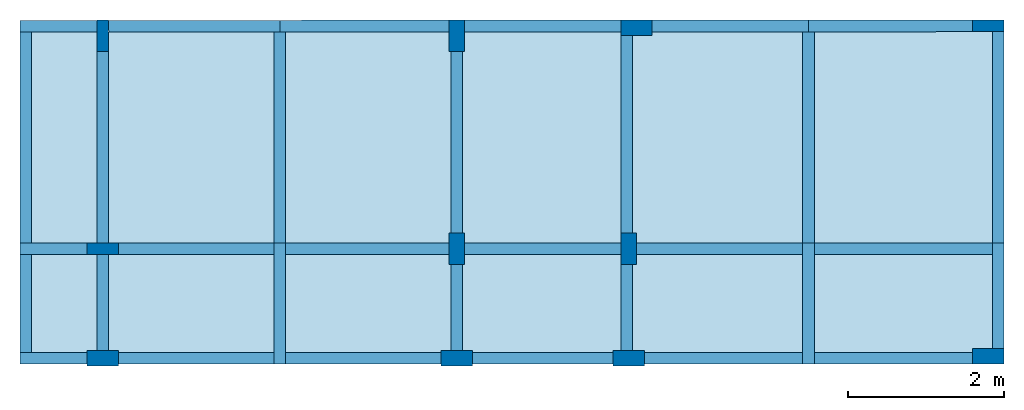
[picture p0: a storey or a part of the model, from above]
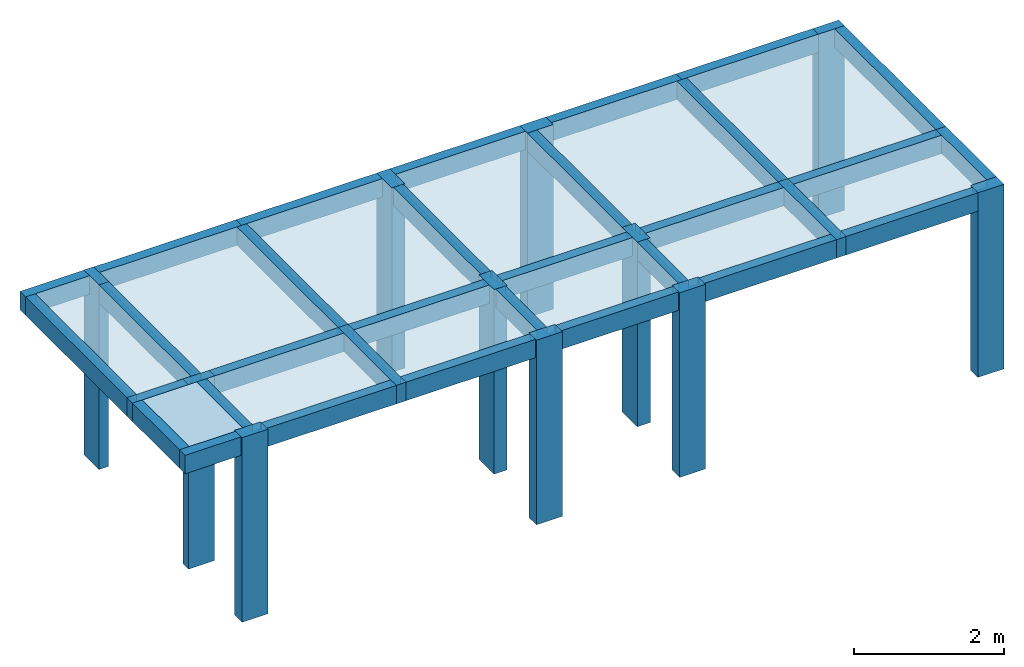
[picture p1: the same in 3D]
Properties of the parts of a building model (IFC2X3)

# File
Description: IFC2X3
Time: 2025-07-01T16:00:53
Made in: IfcPlusPlus

# IfcBuildingStorey (6)
Name | LongName | Elevation (cm)
01. Estacionamento | 01. Estacionamento | 0
02. Térreo | 02. Térreo | 80
03. Pavimento Superior | 03. Pavimento Superior | 400
04. Cobertura | 04. Cobertura | 720
05. Pavimento Técnico | 05. Pavimento Técnico | 1020
06. Laje do Pavimento Técnico | 06. Laje do Pavimento Técnico | 1320

# IfcBeam (464)
Material: Concreto
Pset_ConcreteElementGeneral - EnvironmentalClass: 2; ConstructionType: InSitu
AltoQi_Eberick_Elemento - Elemento: Viga; Tipo: retangular; Elevação: 0 cm
AltoQi_Eberick_Padrão - Ambiente: Externo; Cobrimento: 3 cm; Classe de concreto: C-25
AltoQi_Eberick_Cargas - Cargas de parede (G2): 0; Adicional (G2): 0; Solo (S): 0; Acidental (Q): 0; Água (A): 0; Subpressão (AS): 0
Pset_BeamCommon - IsExternal: yes; LoadBearing: yes
Name | In | Seção_bw (cm) | Seção_h (cm) | Taxa de armadura | Reference
6 x V1 | 02. Térreo | 15 | 40 | 0.17 % | Viga C-25 - Seção Retangular 15 X 40
V1 | 02. Térreo | 15 | 40 | 1.34 % | Viga C-25 - Seção Retangular 15 X 40
V10 | 02. Térreo | 15 | 40 | 0.17 % | Viga C-25 - Seção Retangular 15 X 40
V10 | 02. Térreo | 15 | 40 | 0.26 % | Viga C-25 - Seção Retangular 15 X 40
2 x V11 | 02. Térreo | 15 | 40 | 0.26 % | Viga C-25 - Seção Retangular 15 X 40
V11 | 02. Térreo | 15 | 40 | 0.17 % | Viga C-25 - Seção Retangular 15 X 40
5 x V12 | 02. Térreo | 15 | 40 | 0.17 % | Viga C-25 - Seção Retangular 15 X 40
V13 | 02. Térreo | 15 | 40 | 0.34 % | Viga C-25 - Seção Retangular 15 X 40
V13 | 02. Térreo | 15 | 40 | 0.52 % | Viga C-25 - Seção Retangular 15 X 40
2 x V14 | 02. Térreo | 15 | 40 | 0.34 % | Viga C-25 - Seção Retangular 15 X 40
V14 | 02. Térreo | 15 | 40 | 0.50 % | Viga C-25 - Seção Retangular 15 X 40
V15 | 02. Térreo | 15 | 40 | 0.52 % | Viga C-25 - Seção Retangular 15 X 40
2 x V15 | 02. Térreo | 15 | 40 | 0.26 % | Viga C-25 - Seção Retangular 15 X 40
V16 | 02. Térreo | 15 | 40 | 0.65 % | Viga C-25 - Seção Retangular 15 X 40
V16 | 02. Térreo | 15 | 40 | 0.25 % | Viga C-25 - Seção Retangular 15 X 40
V16 | 02. Térreo | 15 | 40 | 0.41 % | Viga C-25 - Seção Retangular 15 X 40
V17 | 02. Térreo | 15 | 40 | 0.17 % | Viga C-25 - Seção Retangular 15 X 40
V17 | 02. Térreo | 15 | 40 | 0.25 % | Viga C-25 - Seção Retangular 15 X 40
2 x V18 | 02. Térreo | 20 | 40 | 0.59 % | Viga C-25 - Seção Retangular 20 X 40
V18 | 02. Térreo | 20 | 40 | 0.69 % | Viga C-25 - Seção Retangular 20 X 40
4 x V19 | 02. Térreo | 20 | 40 | 0.88 % | Viga C-25 - Seção Retangular 20 X 40
V2 | 02. Térreo | 15 | 40 | 0.34 % | Viga C-25 - Seção Retangular 15 X 40
V2 | 02. Térreo | 15 | 40 | 1.34 % | Viga C-25 - Seção Retangular 15 X 40
2 x V2 | 02. Térreo | 15 | 40 | 0.17 % | Viga C-25 - Seção Retangular 15 X 40
V2 | 02. Térreo | 15 | 40 | 1.02 % | Viga C-25 - Seção Retangular 15 X 40
V20 | 02. Térreo | 20 | 40 | 0.44 % | Viga C-25 - Seção Retangular 20 X 40
2 x V21 | 02. Térreo | 30 | 60 | Não calculado | Viga C-25 - Seção Retangular 30 X 60
V22 | 02. Térreo | 30 | 60 | 0.17 % | Viga C-25 - Seção Retangular 30 X 60
V22 | 02. Térreo | 30 | 60 | 0.26 % | Viga C-25 - Seção Retangular 30 X 60
2 x V23 | 02. Térreo | 30 | 60 | 0.17 % | Viga C-25 - Seção Retangular 30 X 60
2 x V24 | 02. Térreo | 30 | 60 | 0.17 % | Viga C-25 - Seção Retangular 30 X 60
3 x V25 | 02. Térreo | 30 | 60 | Não calculado | Viga C-25 - Seção Retangular 30 X 60
3 x V26 | 02. Térreo | 15 | 40 | 0.59 % | Viga C-25 - Seção Retangular 15 X 40
V27 | 02. Térreo | 15 | 40 | 1.01 % | Viga C-25 - Seção Retangular 15 X 40
V28 | 02. Térreo | 15 | 40 | 0.17 % | Viga C-25 - Seção Retangular 15 X 40
V29 | 02. Térreo | 20 | 40 | Não calculado | Viga C-25 - Seção Retangular 20 X 40
4 x V3 | 02. Térreo | 15 | 40 | 0.17 % | Viga C-25 - Seção Retangular 15 X 40
V33 | 02. Térreo | 25 | 60 | 0.16 % | Viga C-25 - Seção Retangular 25 X 60
2 x V4 | 02. Térreo | 15 | 40 | 0.34 % | Viga C-25 - Seção Retangular 15 X 40
3 x V4 | 02. Térreo | 15 | 40 | 0.17 % | Viga C-25 - Seção Retangular 15 X 40
V4 | 02. Térreo | 15 | 40 | 0.25 % | Viga C-25 - Seção Retangular 15 X 40
2 x V5 | 02. Térreo | 15 | 40 | 0.17 % | Viga C-25 - Seção Retangular 15 X 40
2 x V6 | 02. Térreo | 15 | 40 | 0.17 % | Viga C-25 - Seção Retangular 15 X 40
V8 | 02. Térreo | 15 | 40 | 3.02 % | Viga C-25 - Seção Retangular 15 X 40
2 x V8 | 02. Térreo | 15 | 40 | 1.34 % | Viga C-25 - Seção Retangular 15 X 40
V8 | 02. Térreo | 15 | 40 | 0.79 % | Viga C-25 - Seção Retangular 15 X 40
V8 | 02. Térreo | 15 | 40 | 1.68 % | Viga C-25 - Seção Retangular 15 X 40
V8 | 02. Térreo | 15 | 40 | 0.17 % | Viga C-25 - Seção Retangular 15 X 40
6 x V1 | 03. Pavimento Superior | 15 | 40 | 0.17 % | Viga C-25 - Seção Retangular 15 X 40
5 x V1 | 03. Pavimento Superior | 15 | 40 | 0.92 % | Viga C-25 - Seção Retangular 15 X 40
V10 | 03. Pavimento Superior | 20 | 40 | 0.38 % | Viga C-25 - Seção Retangular 20 X 40
V10 | 03. Pavimento Superior | 20 | 40 | 0.19 % | Viga C-25 - Seção Retangular 20 X 40
V10 | 03. Pavimento Superior | 20 | 40 | 0.88 % | Viga C-25 - Seção Retangular 20 X 40
V10 | 03. Pavimento Superior | 20 | 40 | 0.20 % | Viga C-25 - Seção Retangular 20 X 40
V10 | 03. Pavimento Superior | 20 | 40 | 0.29 % | Viga C-25 - Seção Retangular 20 X 40
V11 | 03. Pavimento Superior | 20 | 40 | 0.19 % | Viga C-25 - Seção Retangular 20 X 40
V12 | 03. Pavimento Superior | 20 | 40 | 0.69 % | Viga C-25 - Seção Retangular 20 X 40
V13 | 03. Pavimento Superior | 20 | 40 | 0.75 % | Viga C-25 - Seção Retangular 20 X 40
V14 | 03. Pavimento Superior | 20 | 40 | 1.23 % | Viga C-25 - Seção Retangular 20 X 40
V15 | 03. Pavimento Superior | 20 | 40 | 0.19 % | Viga C-25 - Seção Retangular 20 X 40
V16 | 03. Pavimento Superior | 15 | 40 | 0.17 % | Viga C-25 - Seção Retangular 15 X 40
V16 | 03. Pavimento Superior | 15 | 40 | 0.26 % | Viga C-25 - Seção Retangular 15 X 40
2 x V17 | 03. Pavimento Superior | 15 | 40 | 0.26 % | Viga C-25 - Seção Retangular 15 X 40
V17 | 03. Pavimento Superior | 15 | 40 | 0.17 % | Viga C-25 - Seção Retangular 15 X 40
6 x V18 | 03. Pavimento Superior | 15 | 40 | 0.17 % | Viga C-25 - Seção Retangular 15 X 40
V19 | 03. Pavimento Superior | 15 | 40 | 0.34 % | Viga C-25 - Seção Retangular 15 X 40
V19 | 03. Pavimento Superior | 15 | 40 | 0.52 % | Viga C-25 - Seção Retangular 15 X 40
V2 | 03. Pavimento Superior | 15 | 40 | 1.23 % | Viga C-25 - Seção Retangular 15 X 40
2 x V2 | 03. Pavimento Superior | 15 | 40 | 0.17 % | Viga C-25 - Seção Retangular 15 X 40
V2 | 03. Pavimento Superior | 15 | 40 | 0.92 % | Viga C-25 - Seção Retangular 15 X 40
V2 | 03. Pavimento Superior | 15 | 40 | 0.26 % | Viga C-25 - Seção Retangular 15 X 40
V20 | 03. Pavimento Superior | 15 | 40 | 0.61 % | Viga C-25 - Seção Retangular 15 X 40
2 x V20 | 03. Pavimento Superior | 15 | 40 | 0.39 % | Viga C-25 - Seção Retangular 15 X 40
V21 | 03. Pavimento Superior | 15 | 40 | 0.50 % | Viga C-25 - Seção Retangular 15 X 40
V21 | 03. Pavimento Superior | 15 | 40 | 0.39 % | Viga C-25 - Seção Retangular 15 X 40
V21 | 03. Pavimento Superior | 15 | 40 | 0.79 % | Viga C-25 - Seção Retangular 15 X 40
V22 | 03. Pavimento Superior | 15 | 40 | 0.79 % | Viga C-25 - Seção Retangular 15 X 40
V22 | 03. Pavimento Superior | 15 | 40 | 0.25 % | Viga C-25 - Seção Retangular 15 X 40
V22 | 03. Pavimento Superior | 15 | 40 | 0.59 % | Viga C-25 - Seção Retangular 15 X 40
V23 | 03. Pavimento Superior | 15 | 40 | 0.17 % | Viga C-25 - Seção Retangular 15 X 40
V23 | 03. Pavimento Superior | 15 | 40 | 0.25 % | Viga C-25 - Seção Retangular 15 X 40
2 x V24 | 03. Pavimento Superior | 20 | 40 | 0.59 % | Viga C-25 - Seção Retangular 20 X 40
V24 | 03. Pavimento Superior | 20 | 40 | 0.92 % | Viga C-25 - Seção Retangular 20 X 40
3 x V25 | 03. Pavimento Superior | 20 | 40 | 0.59 % | Viga C-25 - Seção Retangular 20 X 40
2 x V26 | 03. Pavimento Superior | 20 | 40 | 0.61 % | Viga C-25 - Seção Retangular 20 X 40
2 x V27 | 03. Pavimento Superior | 15 | 40 | 0.34 % | Viga C-25 - Seção Retangular 15 X 40
V28 | 03. Pavimento Superior | 15 | 40 | 0.17 % | Viga C-25 - Seção Retangular 15 X 40
V29 | 03. Pavimento Superior | 15 | 40 | 0.17 % | Viga C-25 - Seção Retangular 15 X 40
3 x V3 | 03. Pavimento Superior | 15 | 40 | 0.17 % | Viga C-25 - Seção Retangular 15 X 40
2 x V30 | 03. Pavimento Superior | 15 | 40 | 0.50 % | Viga C-25 - Seção Retangular 15 X 40
V31 | 03. Pavimento Superior | 15 | 40 | 0.17 % | Viga C-25 - Seção Retangular 15 X 40
3 x V32 | 03. Pavimento Superior | 20 | 45 | 0.61 % | Viga C-25 - Seção Retangular 20 X 45
2 x V32 | 03. Pavimento Superior | 20 | 45 | 0.17 % | Viga C-25 - Seção Retangular 20 X 45
2 x V33 | 03. Pavimento Superior | 20 | 40 | 0.19 % | Viga C-25 - Seção Retangular 20 X 40
V33 | 03. Pavimento Superior | 20 | 40 | 0.44 % | Viga C-25 - Seção Retangular 20 X 40
V34 | 03. Pavimento Superior | 20 | 40 | 0.75 % | Viga C-25 - Seção Retangular 20 X 40
2 x V34 | 03. Pavimento Superior | 20 | 40 | 0.19 % | Viga C-25 - Seção Retangular 20 X 40
V35 | 03. Pavimento Superior | 20 | 40 | 1.01 % | Viga C-25 - Seção Retangular 20 X 40
2 x V35 | 03. Pavimento Superior | 20 | 40 | 0.19 % | Viga C-25 - Seção Retangular 20 X 40
2 x V36 | 03. Pavimento Superior | 20 | 40 | 0.88 % | Viga C-25 - Seção Retangular 20 X 40
V36 | 03. Pavimento Superior | 20 | 40 | 0.19 % | Viga C-25 - Seção Retangular 20 X 40
2 x V37 | 03. Pavimento Superior | 15 | 30 | 0.22 % | Viga C-25 - Seção Retangular 15 X 30
V38 | 03. Pavimento Superior | 20 | 40 | 1.01 % | Viga C-25 - Seção Retangular 20 X 40
V39 | 03. Pavimento Superior | 15 | 40 | 0.17 % | Viga C-25 - Seção Retangular 15 X 40
5 x V4 | 03. Pavimento Superior | 15 | 40 | 0.79 % | Viga C-25 - Seção Retangular 15 X 40
V40 | 03. Pavimento Superior | 20 | 40 | Não calculado | Viga C-25 - Seção Retangular 20 X 40
3 x V5 | 03. Pavimento Superior | 15 | 40 | 0.39 % | Viga C-25 - Seção Retangular 15 X 40
2 x V5 | 03. Pavimento Superior | 15 | 40 | 0.17 % | Viga C-25 - Seção Retangular 15 X 40
V5 | 03. Pavimento Superior | 15 | 40 | 0.25 % | Viga C-25 - Seção Retangular 15 X 40
2 x V6 | 03. Pavimento Superior | 15 | 40 | 1.34 % | Viga C-25 - Seção Retangular 15 X 40
2 x V7 | 03. Pavimento Superior | 15 | 40 | 0.25 % | Viga C-25 - Seção Retangular 15 X 40
2 x V8 | 03. Pavimento Superior | 15 | 40 | 0.17 % | Viga C-25 - Seção Retangular 15 X 40
2 x V9 | 03. Pavimento Superior | 20 | 40 | 0.61 % | Viga C-25 - Seção Retangular 20 X 40
5 x V1 | 04. Cobertura | 15 | 40 | 0.17 % | Viga C-25 - Seção Retangular 15 X 40
3 x V1 | 04. Cobertura | 15 | 40 | 0.82 % | Viga C-25 - Seção Retangular 15 X 40
3 x V10 | 04. Cobertura | 20 | 40 | 0.75 % | Viga C-25 - Seção Retangular 20 X 40
V11 | 04. Cobertura | 20 | 40 | 0.92 % | Viga C-25 - Seção Retangular 20 X 40
V11 | 04. Cobertura | 20 | 40 | 0.20 % | Viga C-25 - Seção Retangular 20 X 40
V11 | 04. Cobertura | 20 | 40 | 0.29 % | Viga C-25 - Seção Retangular 20 X 40
V11 | 04. Cobertura | 20 | 40 | 0.19 % | Viga C-25 - Seção Retangular 20 X 40
V11 | 04. Cobertura | 20 | 40 | 0.39 % | Viga C-25 - Seção Retangular 20 X 40
V12 | 04. Cobertura | 20 | 40 | 0.19 % | Viga C-25 - Seção Retangular 20 X 40
V13 | 04. Cobertura | 20 | 40 | 0.69 % | Viga C-25 - Seção Retangular 20 X 40
V14 | 04. Cobertura | 20 | 40 | 0.69 % | Viga C-25 - Seção Retangular 20 X 40
V15 | 04. Cobertura | 20 | 40 | 1.26 % | Viga C-25 - Seção Retangular 20 X 40
V16 | 04. Cobertura | 20 | 40 | 0.19 % | Viga C-25 - Seção Retangular 20 X 40
V17 | 04. Cobertura | 15 | 40 | 0.17 % | Viga C-25 - Seção Retangular 15 X 40
V17 | 04. Cobertura | 15 | 40 | 0.26 % | Viga C-25 - Seção Retangular 15 X 40
2 x V18 | 04. Cobertura | 15 | 40 | 0.26 % | Viga C-25 - Seção Retangular 15 X 40
V18 | 04. Cobertura | 15 | 40 | 0.17 % | Viga C-25 - Seção Retangular 15 X 40
5 x V19 | 04. Cobertura | 15 | 40 | 0.17 % | Viga C-25 - Seção Retangular 15 X 40
2 x V2 | 04. Cobertura | 15 | 40 | 0.25 % | Viga C-25 - Seção Retangular 15 X 40
V2 | 04. Cobertura | 15 | 40 | 0.17 % | Viga C-25 - Seção Retangular 15 X 40
V2 | 04. Cobertura | 15 | 40 | 1.31 % | Viga C-25 - Seção Retangular 15 X 40
V2 | 04. Cobertura | 15 | 40 | 0.92 % | Viga C-25 - Seção Retangular 15 X 40
V2 | 04. Cobertura | 15 | 40 | 0.26 % | Viga C-25 - Seção Retangular 15 X 40
2 x V20 | 04. Cobertura | 15 | 40 | 0.34 % | Viga C-25 - Seção Retangular 15 X 40
V20 | 04. Cobertura | 15 | 40 | 0.41 % | Viga C-25 - Seção Retangular 15 X 40
V21 | 04. Cobertura | 15 | 40 | 0.34 % | Viga C-25 - Seção Retangular 15 X 40
V21 | 04. Cobertura | 15 | 40 | 0.26 % | Viga C-25 - Seção Retangular 15 X 40
V21 | 04. Cobertura | 15 | 40 | 0.52 % | Viga C-25 - Seção Retangular 15 X 40
V22 | 04. Cobertura | 15 | 40 | 0.39 % | Viga C-25 - Seção Retangular 15 X 40
V22 | 04. Cobertura | 15 | 40 | 0.61 % | Viga C-25 - Seção Retangular 15 X 40
V22 | 04. Cobertura | 15 | 40 | 0.25 % | Viga C-25 - Seção Retangular 15 X 40
V23 | 04. Cobertura | 15 | 40 | 0.17 % | Viga C-25 - Seção Retangular 15 X 40
V23 | 04. Cobertura | 15 | 40 | 0.25 % | Viga C-25 - Seção Retangular 15 X 40
3 x V24 | 04. Cobertura | 20 | 40 | 0.59 % | Viga C-25 - Seção Retangular 20 X 40
3 x V25 | 04. Cobertura | 20 | 40 | 0.59 % | Viga C-25 - Seção Retangular 20 X 40
2 x V26 | 04. Cobertura | 20 | 40 | 0.38 % | Viga C-25 - Seção Retangular 20 X 40
2 x V27 | 04. Cobertura | 15 | 40 | 0.17 % | Viga C-25 - Seção Retangular 15 X 40
3 x V28 | 04. Cobertura | 15 | 30 | 1.57 % | Viga C-25 - Seção Retangular 15 X 30
V29 | 04. Cobertura | 15 | 30 | 0.22 % | Viga C-25 - Seção Retangular 15 X 30
3 x V3 | 04. Cobertura | 15 | 40 | 0.17 % | Viga C-25 - Seção Retangular 15 X 40
2 x V30 | 04. Cobertura | 20 | 40 | 0.19 % | Viga C-25 - Seção Retangular 20 X 40
3 x V30 | 04. Cobertura | 20 | 40 | 0.69 % | Viga C-25 - Seção Retangular 20 X 40
V31 | 04. Cobertura | 15 | 30 | 0.34 % | Viga C-25 - Seção Retangular 15 X 30
2 x V32 | 04. Cobertura | 20 | 40 | 0.19 % | Viga C-25 - Seção Retangular 20 X 40
2 x V32 | 04. Cobertura | 20 | 40 | 0.29 % | Viga C-25 - Seção Retangular 20 X 40
V33 | 04. Cobertura | 20 | 40 | 0.49 % | Viga C-25 - Seção Retangular 20 X 40
2 x V33 | 04. Cobertura | 20 | 40 | 0.19 % | Viga C-25 - Seção Retangular 20 X 40
2 x V34 | 04. Cobertura | 20 | 40 | 0.19 % | Viga C-25 - Seção Retangular 20 X 40
V34 | 04. Cobertura | 20 | 40 | 0.61 % | Viga C-25 - Seção Retangular 20 X 40
2 x V35 | 04. Cobertura | 20 | 40 | 0.49 % | Viga C-25 - Seção Retangular 20 X 40
V35 | 04. Cobertura | 20 | 40 | 0.19 % | Viga C-25 - Seção Retangular 20 X 40
2 x V36 | 04. Cobertura | 15 | 30 | 0.22 % | Viga C-25 - Seção Retangular 15 X 30
V37 | 04. Cobertura | 15 | 40 | 0.79 % | Viga C-25 - Seção Retangular 15 X 40
V38 | 04. Cobertura | 15 | 40 | 0.17 % | Viga C-25 - Seção Retangular 15 X 40
V39 | 04. Cobertura | 15 | 40 | Não calculado | Viga C-25 - Seção Retangular 15 X 40
3 x V4 | 04. Cobertura | 15 | 30 | 0.82 % | Viga C-25 - Seção Retangular 15 X 30
3 x V5 | 04. Cobertura | 15 | 40 | 0.34 % | Viga C-25 - Seção Retangular 15 X 40
V5 | 04. Cobertura | 15 | 40 | 0.17 % | Viga C-25 - Seção Retangular 15 X 40
V5 | 04. Cobertura | 15 | 40 | 0.26 % | Viga C-25 - Seção Retangular 15 X 40
2 x V6 | 04. Cobertura | 15 | 40 | 1.31 % | Viga C-25 - Seção Retangular 15 X 40
2 x V7 | 04. Cobertura | 15 | 30 | 0.87 % | Viga C-25 - Seção Retangular 15 X 30
2 x V8 | 04. Cobertura | 15 | 40 | 0.17 % | Viga C-25 - Seção Retangular 15 X 40
2 x V9 | 04. Cobertura | 15 | 40 | 0.17 % | Viga C-25 - Seção Retangular 15 X 40
5 x V1 | 05. Pavimento Técnico | 15 | 30 | 0.22 % | Viga C-25 - Seção Retangular 15 X 30
4 x V1 | 05. Pavimento Técnico | 15 | 30 | 2.68 % | Viga C-25 - Seção Retangular 15 X 30
2 x V1 | 05. Pavimento Técnico | 15 | 30 | 0.45 % | Viga C-25 - Seção Retangular 15 X 30
2 x V1 | 05. Pavimento Técnico | 15 | 30 | 0.34 % | Viga C-25 - Seção Retangular 15 X 30
2 x V1 | 05. Pavimento Técnico | 15 | 30 | 0.70 % | Viga C-25 - Seção Retangular 15 X 30
2 x V10 | 05. Pavimento Técnico | 15 | 40 | 0.17 % | Viga C-25 - Seção Retangular 15 X 40
7 x V11 | 05. Pavimento Técnico | 15 | 30 | 0.22 % | Viga C-25 - Seção Retangular 15 X 30
4 x V11 | 05. Pavimento Técnico | 15 | 30 | 1.34 % | Viga C-25 - Seção Retangular 15 X 30
2 x V11 | 05. Pavimento Técnico | 15 | 30 | 0.45 % | Viga C-25 - Seção Retangular 15 X 30
V11 | 05. Pavimento Técnico | 15 | 30 | 0.34 % | Viga C-25 - Seção Retangular 15 X 30
6 x V12 | 05. Pavimento Técnico | 20 | 40 | 0.19 % | Viga C-25 - Seção Retangular 20 X 40
V12 | 05. Pavimento Técnico | 20 | 40 | 0.25 % | Viga C-25 - Seção Retangular 20 X 40
5 x V13 | 05. Pavimento Técnico | 15 | 30 | 0.22 % | Viga C-25 - Seção Retangular 15 X 30
4 x V14 | 05. Pavimento Técnico | 15 | 30 | 0.67 % | Viga C-25 - Seção Retangular 15 X 30
2 x V14 | 05. Pavimento Técnico | 15 | 30 | 0.22 % | Viga C-25 - Seção Retangular 15 X 30
3 x V15 | 05. Pavimento Técnico | 15 | 30 | 0.52 % | Viga C-25 - Seção Retangular 15 X 30
3 x V15 | 05. Pavimento Técnico | 15 | 30 | 0.22 % | Viga C-25 - Seção Retangular 15 X 30
V15 | 05. Pavimento Técnico | 15 | 30 | 0.34 % | Viga C-25 - Seção Retangular 15 X 30
2 x V16 | 05. Pavimento Técnico | 15 | 30 | 0.22 % | Viga C-25 - Seção Retangular 15 X 30
V16 | 05. Pavimento Técnico | 15 | 30 | 0.34 % | Viga C-25 - Seção Retangular 15 X 30
2 x V16 | 05. Pavimento Técnico | 15 | 30 | 0.70 % | Viga C-25 - Seção Retangular 15 X 30
V16 | 05. Pavimento Técnico | 15 | 30 | 0.35 % | Viga C-25 - Seção Retangular 15 X 30
4 x V17 | 05. Pavimento Técnico | 20 | 40 | 0.25 % | Viga C-25 - Seção Retangular 20 X 40
2 x V17 | 05. Pavimento Técnico | 20 | 40 | 0.19 % | Viga C-25 - Seção Retangular 20 X 40
2 x V18 | 05. Pavimento Técnico | 20 | 40 | 0.19 % | Viga C-25 - Seção Retangular 20 X 40
3 x V18 | 05. Pavimento Técnico | 20 | 40 | 1.18 % | Viga C-25 - Seção Retangular 20 X 40
V18 | 05. Pavimento Técnico | 20 | 40 | 0.31 % | Viga C-25 - Seção Retangular 20 X 40
V19 | 05. Pavimento Técnico | 20 | 40 | 0.19 % | Viga C-25 - Seção Retangular 20 X 40
4 x V19 | 05. Pavimento Técnico | 20 | 40 | 0.39 % | Viga C-25 - Seção Retangular 20 X 40
V2 | 05. Pavimento Técnico | 15 | 30 | 0.22 % | Viga C-25 - Seção Retangular 15 X 30
2 x V20 | 05. Pavimento Técnico | 15 | 30 | 0.35 % | Viga C-25 - Seção Retangular 15 X 30
V20 | 05. Pavimento Técnico | 15 | 30 | 0.22 % | Viga C-25 - Seção Retangular 15 X 30
2 x V21 | 05. Pavimento Técnico | 15 | 30 | 1.22 % | Viga C-25 - Seção Retangular 15 X 30
V21 | 05. Pavimento Técnico | 15 | 30 | 0.22 % | Viga C-25 - Seção Retangular 15 X 30
V22 | 05. Pavimento Técnico | 20 | 40 | 0.19 % | Viga C-25 - Seção Retangular 20 X 40
2 x V23 | 05. Pavimento Técnico | 20 | 45 | 1.13 % | Viga C-25 - Seção Retangular 20 X 45
3 x V24 | 05. Pavimento Técnico | 15 | 30 | 0.22 % | Viga C-25 - Seção Retangular 15 X 30
V25 | 05. Pavimento Técnico | 15 | 30 | 0.22 % | Viga C-25 - Seção Retangular 15 X 30
2 x V26 | 05. Pavimento Técnico | 20 | 40 | 0.61 % | Viga C-25 - Seção Retangular 20 X 40
3 x V27 | 05. Pavimento Técnico | 15 | 30 | 0.22 % | Viga C-25 - Seção Retangular 15 X 30
V28 | 05. Pavimento Técnico | 15 | 30 | 0.22 % | Viga C-25 - Seção Retangular 15 X 30
2 x V29 | 05. Pavimento Técnico | 20 | 45 | 1.06 % | Viga C-25 - Seção Retangular 20 X 45
3 x V3 | 05. Pavimento Técnico | 20 | 40 | 0.25 % | Viga C-25 - Seção Retangular 20 X 40
3 x V3 | 05. Pavimento Técnico | 20 | 40 | 0.19 % | Viga C-25 - Seção Retangular 20 X 40
V30 | 05. Pavimento Técnico | 15 | 30 | 0.22 % | Viga C-25 - Seção Retangular 15 X 30
2 x V30 | 05. Pavimento Técnico | 15 | 30 | 0.34 % | Viga C-25 - Seção Retangular 15 X 30
3 x V31 | 05. Pavimento Técnico | 15 | 30 | 0.34 % | Viga C-25 - Seção Retangular 15 X 30
V32 | 05. Pavimento Técnico | 15 | 30 | 0.22 % | Viga C-25 - Seção Retangular 15 X 30
V33 | 05. Pavimento Técnico | 15 | 30 | 0.34 % | Viga C-25 - Seção Retangular 15 X 30
3 x V4 | 05. Pavimento Técnico | 20 | 45 | 1.22 % | Viga C-25 - Seção Retangular 20 X 45
4 x V4 | 05. Pavimento Técnico | 20 | 45 | 0.17 % | Viga C-25 - Seção Retangular 20 X 45
2 x V4 | 05. Pavimento Técnico | 20 | 45 | 0.55 % | Viga C-25 - Seção Retangular 20 X 45
V5 | 05. Pavimento Técnico | 15 | 30 | 0.22 % | Viga C-25 - Seção Retangular 15 X 30
7 x V6 | 05. Pavimento Técnico | 20 | 40 | Não calculado | Viga C-25 - Seção Retangular 20 X 40
V7 | 05. Pavimento Técnico | 15 | 30 | 0.22 % | Viga C-25 - Seção Retangular 15 X 30
2 x V8 | 05. Pavimento Técnico | 15 | 30 | 0.22 % | Viga C-25 - Seção Retangular 15 X 30
2 x V9 | 05. Pavimento Técnico | 15 | 30 | 0.89 % | Viga C-25 - Seção Retangular 15 X 30
2 x V1 | 06. Laje do Pavimento Técnico | 15 | 30 | 0.67 % | Viga C-25 - Seção Retangular 15 X 30
3 x V1 | 06. Laje do Pavimento Técnico | 15 | 30 | 0.45 % | Viga C-25 - Seção Retangular 15 X 30
V1 | 06. Laje do Pavimento Técnico | 15 | 30 | 0.22 % | Viga C-25 - Seção Retangular 15 X 30
2 x V10 | 06. Laje do Pavimento Técnico | 15 | 30 | 0.45 % | Viga C-25 - Seção Retangular 15 X 30
2 x V2 | 06. Laje do Pavimento Técnico | 15 | 30 | 0.67 % | Viga C-25 - Seção Retangular 15 X 30
2 x V2 | 06. Laje do Pavimento Técnico | 15 | 30 | 0.22 % | Viga C-25 - Seção Retangular 15 X 30
2 x V2 | 06. Laje do Pavimento Técnico | 15 | 30 | 0.45 % | Viga C-25 - Seção Retangular 15 X 30
2 x V3 | 06. Laje do Pavimento Técnico | 15 | 30 | 0.55 % | Viga C-25 - Seção Retangular 15 X 30
4 x V3 | 06. Laje do Pavimento Técnico | 15 | 30 | 0.22 % | Viga C-25 - Seção Retangular 15 X 30
2 x V4 | 06. Laje do Pavimento Técnico | 15 | 30 | 0.22 % | Viga C-25 - Seção Retangular 15 X 30
V5 | 06. Laje do Pavimento Técnico | 15 | 30 | 0.34 % | Viga C-25 - Seção Retangular 15 X 30
V5 | 06. Laje do Pavimento Técnico | 15 | 30 | 0.22 % | Viga C-25 - Seção Retangular 15 X 30
2 x V6 | 06. Laje do Pavimento Técnico | 15 | 30 | 0.22 % | Viga C-25 - Seção Retangular 15 X 30
V7 | 06. Laje do Pavimento Técnico | 15 | 30 | 0.45 % | Viga C-25 - Seção Retangular 15 X 30
V7 | 06. Laje do Pavimento Técnico | 15 | 30 | 0.34 % | Viga C-25 - Seção Retangular 15 X 30
V8 | 06. Laje do Pavimento Técnico | 15 | 30 | 0.34 % | Viga C-25 - Seção Retangular 15 X 30
V8 | 06. Laje do Pavimento Técnico | 15 | 30 | 0.89 % | Viga C-25 - Seção Retangular 15 X 30
2 x V9 | 06. Laje do Pavimento Técnico | 15 | 30 | 0.22 % | Viga C-25 - Seção Retangular 15 X 30

# IfcColumn (176)
Material: Concreto
Pset_ConcreteElementGeneral - EnvironmentalClass: 2; ConstructionType: InSitu
AltoQi_Eberick_Elemento - Elemento: Pilar; Elevação: 0 cm
AltoQi_Eberick_Padrão - Ambiente: Externo; Cobrimento: 3 cm; Classe de concreto: C-25
Pset_ColumnCommon - IsExternal: yes; LoadBearing: yes
Name | In | Tipo | Seção_b (cm) | Seção_h (cm) | Taxa de armadura | Taxa de compressão bruta | Taxa de compressão homogeneizada | Reference
P1 | 01. Estacionamento | retangular | 15 | 40 | 1.83 % | 0.04 | 0.03 | Pilar C-25 - Retangular 15x40
P10 | 01. Estacionamento | retangular | 30 | 60 | 0.41 % | 0.15 | 0.14 | Pilar C-25 - Retangular 30x60
P11 | 01. Estacionamento | retangular | 20 | 40 | 0.59 % | 0.2 | 0.18 | Pilar C-25 - Retangular 20x40
P12 | 01. Estacionamento | retangular | 20 | 45 | 1.22 % | 0.23 | 0.2 | Pilar C-25 - Retangular 20x45
P13 | 01. Estacionamento | retangular | 20 | 45 | 1.22 % | 0.23 | 0.2 | Pilar C-25 - Retangular 20x45
P14 | 01. Estacionamento | retangular | 20 | 40 | 1.77 % | 0.09 | 0.07 | Pilar C-25 - Retangular 20x40
P15 | 01. Estacionamento | retangular | 20 | 40 | 2.36 % | 0.03 | 0.03 | Pilar C-25 - Retangular 20x40
P16 | 01. Estacionamento | retangular | 15 | 40 | 1.83 % | 0.05 | 0.04 | Pilar C-25 - Retangular 15x40
P17 | 01. Estacionamento | retangular | 25 | 50 | 0.50 % | 0.15 | 0.14 | Pilar C-25 - Retangular 25x50
P18 | 01. Estacionamento | retangular | 25 | 50 | 0.50 % | 0.14 | 0.13 | Pilar C-25 - Retangular 25x50
P19 | 01. Estacionamento | retangular | 25 | 50 | 0.50 % | 0.13 | 0.12 | Pilar C-25 - Retangular 25x50
P2 | 01. Estacionamento | retangular | 15 | 40 | 1.57 % | 0.14 | 0.11 | Pilar C-25 - Retangular 15x40
P20 | 01. Estacionamento | retangular | 30 | 60 | 0.41 % | 0.15 | 0.13 | Pilar C-25 - Retangular 30x60
P21 | 01. Estacionamento | retangular | 35 | 60 | 0.45 % | 0.25 | 0.24 | Pilar C-25 - Retangular 35x60
P22 | 01. Estacionamento | retangular | 20 | 40 | 0.98 % | 0.16 | 0.13 | Pilar C-25 - Retangular 20x40
P23 | 01. Estacionamento | retangular | 20 | 40 | 1.37 % | 0.08 | 0.07 | Pilar C-25 - Retangular 20x40
P28 | 01. Estacionamento | seção circular | 5 | 60 | 0.42 % | 0.19 | 0.17 | Pilar C-25 - Seção Circular 60x5
P29 | 01. Estacionamento | seção circular | 5 | 45 | 0.85 % | 0.27 | 0.23 | Pilar C-25 - Seção Circular 45x5
P3 | 01. Estacionamento | retangular | 15 | 40 | 1.05 % | 0.13 | 0.11 | Pilar C-25 - Retangular 15x40
P30 | 01. Estacionamento | seção circular | 5 | 60 | 0.42 % | 0.22 | 0.2 | Pilar C-25 - Seção Circular 60x5
P31 | 01. Estacionamento | seção circular | 5 | 60 | 0.42 % | 0.18 | 0.16 | Pilar C-25 - Seção Circular 60x5
P32 | 01. Estacionamento | seção circular | 5 | 60 | 0.42 % | 0.13 | 0.11 | Pilar C-25 - Seção Circular 60x5
P33 | 01. Estacionamento | retangular | 15 | 40 | 2.09 % | 0.24 | 0.19 | Pilar C-25 - Retangular 15x40
P34 | 01. Estacionamento | retangular | 30 | 60 | 0.41 % | 0.08 | 0.08 | Pilar C-25 - Retangular 30x60
P35 | 01. Estacionamento | retangular | 15 | 40 | 1.31 % | 0.03 | 0.02 | Pilar C-25 - Retangular 15x40
P36 | 01. Estacionamento | retangular | 15 | 40 | 1.23 % | 0.2 | 0.16 | Pilar C-25 - Retangular 15x40
P37 | 01. Estacionamento | retangular | 15 | 40 | 1.64 % | 0.14 | 0.11 | Pilar C-25 - Retangular 15x40
P38 | 01. Estacionamento | retangular | 15 | 40 | 1.64 % | 0.15 | 0.11 | Pilar C-25 - Retangular 15x40
P39 | 01. Estacionamento | retangular | 30 | 60 | 0.41 % | 0.1 | 0.09 | Pilar C-25 - Retangular 30x60
P4 | 01. Estacionamento | retangular | 15 | 40 | 1.57 % | 0.12 | 0.1 | Pilar C-25 - Retangular 15x40
P40 | 01. Estacionamento | retangular | 30 | 60 | 0.41 % | 0.13 | 0.12 | Pilar C-25 - Retangular 30x60
P5 | 01. Estacionamento | retangular | 20 | 40 | 1.96 % | 0.05 | 0.04 | Pilar C-25 - Retangular 20x40
P6 | 01. Estacionamento | retangular | 25 | 50 | 0.50 % | 0.18 | 0.16 | Pilar C-25 - Retangular 25x50
P8 | 01. Estacionamento | retangular | 30 | 60 | 0.41 % | 0.17 | 0.16 | Pilar C-25 - Retangular 30x60
P9 | 01. Estacionamento | retangular | 30 | 60 | 0.41 % | 0.15 | 0.14 | Pilar C-25 - Retangular 30x60
P1 | 02. Térreo | retangular | 15 | 40 | 0.79 % | 0.04 | 0.03 | Pilar C-25 - Retangular 15x40
P10 | 02. Térreo | retangular | 20 | 40 | 0.59 % | 0.35 | 0.31 | Pilar C-25 - Retangular 20x40
P11 | 02. Térreo | retangular | 20 | 40 | 0.59 % | 0.2 | 0.18 | Pilar C-25 - Retangular 20x40
P12 | 02. Térreo | retangular | 20 | 45 | 0.52 % | 0.23 | 0.21 | Pilar C-25 - Retangular 20x45
P13 | 02. Térreo | retangular | 20 | 45 | 0.52 % | 0.23 | 0.21 | Pilar C-25 - Retangular 20x45
P14 | 02. Térreo | retangular | 20 | 40 | 0.59 % | 0.09 | 0.08 | Pilar C-25 - Retangular 20x40
P15 | 02. Térreo | retangular | 20 | 40 | 1.18 % | 0.03 | 0.03 | Pilar C-25 - Retangular 20x40
P16 | 02. Térreo | retangular | 15 | 40 | 0.79 % | 0.05 | 0.04 | Pilar C-25 - Retangular 15x40
P17 | 02. Térreo | retangular | 15 | 40 | 0.79 % | 0.31 | 0.27 | Pilar C-25 - Retangular 15x40
P18 | 02. Térreo | retangular | 15 | 40 | 0.79 % | 0.28 | 0.25 | Pilar C-25 - Retangular 15x40
P19 | 02. Térreo | retangular | 15 | 40 | 1.23 % | 0.28 | 0.22 | Pilar C-25 - Retangular 15x40
P2 | 02. Térreo | retangular | 15 | 40 | 0.79 % | 0.13 | 0.12 | Pilar C-25 - Retangular 15x40
P20 | 02. Térreo | retangular | 20 | 40 | 0.59 % | 0.32 | 0.29 | Pilar C-25 - Retangular 20x40
P21 | 02. Térreo | retangular | 20 | 45 | 1.05 % | 0.59 | 0.51 | Pilar C-25 - Retangular 20x45
P22 | 02. Térreo | retangular | 20 | 40 | 0.59 % | 0.15 | 0.14 | Pilar C-25 - Retangular 20x40
P23 | 02. Térreo | retangular | 20 | 40 | 0.59 % | 0.08 | 0.07 | Pilar C-25 - Retangular 20x40
P28 | 02. Térreo | seção circular | 5 | 45 | 0.40 % | 0.34 | 0.31 | Pilar C-25 - Seção Circular 45x5
P29 | 02. Térreo | seção circular | 5 | 45 | 0.40 % | 0.27 | 0.25 | Pilar C-25 - Seção Circular 45x5
P3 | 02. Térreo | retangular | 15 | 40 | 0.79 % | 0.13 | 0.11 | Pilar C-25 - Retangular 15x40
P30 | 02. Térreo | seção circular | 5 | 45 | 0.40 % | 0.39 | 0.36 | Pilar C-25 - Seção Circular 45x5
P31 | 02. Térreo | seção circular | 5 | 40 | 0.69 % | 0.41 | 0.35 | Pilar C-25 - Seção Circular 40x5
P32 | 02. Térreo | seção circular | 5 | 40 | 0.38 % | 0.28 | 0.26 | Pilar C-25 - Seção Circular 40x5
P33 | 02. Térreo | retangular | 15 | 40 | 0.79 % | 0.24 | 0.21 | Pilar C-25 - Retangular 15x40
P34 | 02. Térreo | retangular | 15 | 40 | 0.79 % | 0.25 | 0.22 | Pilar C-25 - Retangular 15x40
P35 | 02. Térreo | retangular | 15 | 40 | 0.79 % | 0.02 | 0.02 | Pilar C-25 - Retangular 15x40
P36 | 02. Térreo | retangular | 15 | 40 | 1.23 % | 0.19 | 0.16 | Pilar C-25 - Retangular 15x40
P37 | 02. Térreo | retangular | 15 | 40 | 1.23 % | 0.14 | 0.11 | Pilar C-25 - Retangular 15x40
P38 | 02. Térreo | retangular | 15 | 40 | 1.23 % | 0.14 | 0.12 | Pilar C-25 - Retangular 15x40
P39 | 02. Térreo | retangular | 20 | 40 | 0.79 % | 0.22 | 0.2 | Pilar C-25 - Retangular 20x40
P4 | 02. Térreo | retangular | 15 | 40 | 0.79 % | 0.12 | 0.1 | Pilar C-25 - Retangular 15x40
P40 | 02. Térreo | retangular | 20 | 40 | 0.79 % | 0.28 | 0.25 | Pilar C-25 - Retangular 20x40
P5 | 02. Térreo | retangular | 20 | 40 | 0.98 % | 0.05 | 0.04 | Pilar C-25 - Retangular 20x40
P6 | 02. Térreo | retangular | 20 | 40 | 1.51 % | 0.27 | 0.21 | Pilar C-25 - Retangular 20x40
P8 | 02. Térreo | retangular | 20 | 45 | 1.34 % | 0.33 | 0.26 | Pilar C-25 - Retangular 20x45
P9 | 02. Térreo | retangular | 20 | 45 | 0.89 % | 0.29 | 0.24 | Pilar C-25 - Retangular 20x45
P1 | 03. Pavimento Superior | retangular | 15 | 40 | 1.57 % | 0.02 | 0.02 | Pilar C-25 - Retangular 15x40
P10 | 03. Pavimento Superior | retangular | 20 | 40 | 1.57 % | 0.25 | 0.19 | Pilar C-25 - Retangular 20x40
P11 | 03. Pavimento Superior | retangular | 20 | 40 | 0.59 % | 0.15 | 0.13 | Pilar C-25 - Retangular 20x40
P12 | 03. Pavimento Superior | retangular | 20 | 45 | 2.09 % | 0.15 | 0.11 | Pilar C-25 - Retangular 20x45
P13 | 03. Pavimento Superior | retangular | 20 | 45 | 2.09 % | 0.14 | 0.1 | Pilar C-25 - Retangular 20x45
P14 | 03. Pavimento Superior | retangular | 20 | 40 | 2.16 % | 0.06 | 0.05 | Pilar C-25 - Retangular 20x40
P15 | 03. Pavimento Superior | retangular | 20 | 40 | 2.76 % | 0.03 | 0.02 | Pilar C-25 - Retangular 20x40
P16 | 03. Pavimento Superior | retangular | 15 | 40 | 2.62 % | 0.03 | 0.02 | Pilar C-25 - Retangular 15x40
P17 | 03. Pavimento Superior | retangular | 15 | 40 | 2.01 % | 0.23 | 0.17 | Pilar C-25 - Retangular 15x40
P18 | 03. Pavimento Superior | retangular | 15 | 40 | 1.31 % | 0.21 | 0.17 | Pilar C-25 - Retangular 15x40
P19 | 03. Pavimento Superior | retangular | 15 | 40 | 2.05 % | 0.23 | 0.17 | Pilar C-25 - Retangular 15x40
P2 | 03. Pavimento Superior | retangular | 15 | 40 | 1.23 % | 0.1 | 0.08 | Pilar C-25 - Retangular 15x40
P20 | 03. Pavimento Superior | retangular | 20 | 40 | 1.23 % | 0.23 | 0.19 | Pilar C-25 - Retangular 20x40
P21 | 03. Pavimento Superior | retangular | 20 | 45 | 2.44 % | 0.54 | 0.41 | Pilar C-25 - Retangular 20x45
P22 | 03. Pavimento Superior | retangular | 20 | 40 | 1.77 % | 0.11 | 0.09 | Pilar C-25 - Retangular 20x40
P23 | 03. Pavimento Superior | retangular | 20 | 40 | 1.84 % | 0.06 | 0.05 | Pilar C-25 - Retangular 20x40
P28 | 03. Pavimento Superior | seção circular | 5 | 45 | 0.40 % | 0.27 | 0.25 | Pilar C-25 - Seção Circular 45x5
P29 | 03. Pavimento Superior | seção circular | 5 | 45 | 0.45 % | 0.23 | 0.21 | Pilar C-25 - Seção Circular 45x5
P3 | 03. Pavimento Superior | retangular | 15 | 40 | 1.57 % | 0.1 | 0.08 | Pilar C-25 - Retangular 15x40
P30 | 03. Pavimento Superior | seção circular | 5 | 45 | 0.40 % | 0.33 | 0.3 | Pilar C-25 - Seção Circular 45x5
P31 | 03. Pavimento Superior | seção circular | 5 | 40 | 1.78 % | 0.32 | 0.23 | Pilar C-25 - Seção Circular 40x5
P32 | 03. Pavimento Superior | seção circular | 5 | 40 | 1.33 % | 0.22 | 0.17 | Pilar C-25 - Seção Circular 40x5
P33 | 03. Pavimento Superior | retangular | 15 | 40 | 2.62 % | 0.18 | 0.13 | Pilar C-25 - Retangular 15x40
P34 | 03. Pavimento Superior | retangular | 15 | 40 | 2.68 % | 0.19 | 0.13 | Pilar C-25 - Retangular 15x40
P35 | 03. Pavimento Superior | retangular | 15 | 40 | 1.05 % | 0.01 | 0.01 | Pilar C-25 - Retangular 15x40
P36 | 03. Pavimento Superior | retangular | 15 | 40 | 2.05 % | 0.15 | 0.12 | Pilar C-25 - Retangular 15x40
P37 | 03. Pavimento Superior | retangular | 15 | 40 | 1.83 % | 0.11 | 0.09 | Pilar C-25 - Retangular 15x40
P38 | 03. Pavimento Superior | retangular | 15 | 40 | 1.83 % | 0.12 | 0.1 | Pilar C-25 - Retangular 15x40
P39 | 03. Pavimento Superior | retangular | 20 | 40 | 1.53 % | 0.16 | 0.13 | Pilar C-25 - Retangular 20x40
P4 | 03. Pavimento Superior | retangular | 15 | 40 | 1.05 % | 0.1 | 0.09 | Pilar C-25 - Retangular 15x40
P40 | 03. Pavimento Superior | retangular | 20 | 40 | 1.51 % | 0.25 | 0.19 | Pilar C-25 - Retangular 20x40
P5 | 03. Pavimento Superior | retangular | 20 | 40 | 1.57 % | 0.04 | 0.03 | Pilar C-25 - Retangular 20x40
P6 | 03. Pavimento Superior | retangular | 20 | 40 | 1.96 % | 0.19 | 0.15 | Pilar C-25 - Retangular 20x40
P8 | 03. Pavimento Superior | retangular | 20 | 45 | 2.44 % | 0.25 | 0.19 | Pilar C-25 - Retangular 20x45
P9 | 03. Pavimento Superior | retangular | 20 | 45 | 1.40 % | 0.22 | 0.16 | Pilar C-25 - Retangular 20x45
P10 | 04. Cobertura | retangular | 20 | 40 | 1.96 % | 0.17 | 0.13 | Pilar C-25 - Retangular 20x40
P11 | 04. Cobertura | retangular | 20 | 40 | 0.79 % | 0.09 | 0.08 | Pilar C-25 - Retangular 20x40
P12 | 04. Cobertura | retangular | 20 | 45 | 4.47 % | 0.08 | 0.05 | Pilar C-25 - Retangular 20x45
P13 | 04. Cobertura | retangular | 20 | 45 | 4.47 % | 0.07 | 0.05 | Pilar C-25 - Retangular 20x45
P14 | 04. Cobertura | retangular | 20 | 40 | 2.76 % | 0.04 | 0.03 | Pilar C-25 - Retangular 20x40
P15 | 04. Cobertura | retangular | 20 | 40 | 1.84 % | 0.03 | 0.02 | Pilar C-25 - Retangular 20x40
P17 | 04. Cobertura | retangular | 15 | 40 | 3.27 % | 0.15 | 0.1 | Pilar C-25 - Retangular 15x40
P18 | 04. Cobertura | retangular | 15 | 40 | 1.23 % | 0.14 | 0.11 | Pilar C-25 - Retangular 15x40
P19 | 04. Cobertura | retangular | 15 | 40 | 2.05 % | 0.18 | 0.14 | Pilar C-25 - Retangular 15x40
P2 | 04. Cobertura | retangular | 15 | 40 | 1.23 % | 0.05 | 0.04 | Pilar C-25 - Retangular 15x40
P20 | 04. Cobertura | retangular | 20 | 40 | 1.23 % | 0.16 | 0.13 | Pilar C-25 - Retangular 20x40
P21 | 04. Cobertura | retangular | 20 | 45 | 2.73 % | 0.41 | 0.3 | Pilar C-25 - Retangular 20x45
P22 | 04. Cobertura | retangular | 20 | 40 | 2.76 % | 0.06 | 0.05 | Pilar C-25 - Retangular 20x40
P23 | 04. Cobertura | retangular | 20 | 40 | 1.57 % | 0.04 | 0.04 | Pilar C-25 - Retangular 20x40
P28 | 04. Cobertura | seção circular | 5 | 45 | 0.45 % | 0.19 | 0.17 | Pilar C-25 - Seção Circular 45x5
P29 | 04. Cobertura | seção circular | 5 | 45 | 0.40 % | 0.15 | 0.14 | Pilar C-25 - Seção Circular 45x5
P3 | 04. Cobertura | retangular | 15 | 40 | 1.57 % | 0.06 | 0.05 | Pilar C-25 - Retangular 15x40
P30 | 04. Cobertura | seção circular | 5 | 45 | 0.40 % | 0.23 | 0.21 | Pilar C-25 - Seção Circular 45x5
P31 | 04. Cobertura | seção circular | 5 | 40 | 3.90 % | 0.16 | 0.09 | Pilar C-25 - Seção Circular 40x5
P32 | 04. Cobertura | seção circular | 5 | 40 | 3.74 % | 0.11 | 0.06 | Pilar C-25 - Seção Circular 40x5
P33 | 04. Cobertura | retangular | 15 | 40 | 1.83 % | 0.12 | 0.09 | Pilar C-25 - Retangular 15x40
P34 | 04. Cobertura | retangular | 15 | 40 | 2.01 % | 0.13 | 0.09 | Pilar C-25 - Retangular 15x40
P36 | 04. Cobertura | retangular | 15 | 40 | 2.36 % | 0.11 | 0.08 | Pilar C-25 - Retangular 15x40
P37 | 04. Cobertura | retangular | 15 | 40 | 1.57 % | 0.07 | 0.06 | Pilar C-25 - Retangular 15x40
P38 | 04. Cobertura | retangular | 15 | 40 | 2.01 % | 0.1 | 0.08 | Pilar C-25 - Retangular 15x40
P39 | 04. Cobertura | retangular | 20 | 40 | 2.45 % | 0.1 | 0.07 | Pilar C-25 - Retangular 20x40
P4 | 04. Cobertura | retangular | 15 | 40 | 0.79 % | 0.08 | 0.07 | Pilar C-25 - Retangular 15x40
P40 | 04. Cobertura | retangular | 20 | 40 | 1.37 % | 0.2 | 0.17 | Pilar C-25 - Retangular 20x40
P5 | 04. Cobertura | retangular | 20 | 40 | 1.18 % | 0.03 | 0.03 | Pilar C-25 - Retangular 20x40
P6 | 04. Cobertura | retangular | 20 | 40 | 1.18 % | 0.15 | 0.13 | Pilar C-25 - Retangular 20x40
P8 | 04. Cobertura | retangular | 20 | 45 | 1.75 % | 0.17 | 0.14 | Pilar C-25 - Retangular 20x45
P9 | 04. Cobertura | retangular | 20 | 45 | 1.05 % | 0.14 | 0.12 | Pilar C-25 - Retangular 20x45
P10 | 05. Pavimento Técnico | retangular | 20 | 40 | 1.84 % | 0.08 | 0.06 | Pilar C-25 - Retangular 20x40
P11 | 05. Pavimento Técnico | retangular | 20 | 40 | 3.37 % | 0.05 | 0.03 | Pilar C-25 - Retangular 20x40
P14 | 05. Pavimento Técnico | retangular | 20 | 40 | 1.23 % | 0.03 | 0.02 | Pilar C-25 - Retangular 20x40
P15 | 05. Pavimento Técnico | retangular | 15 | 40 | 1.57 % | 0.03 | 0.02 | Pilar C-25 - Retangular 15x40
P17 | 05. Pavimento Técnico | retangular | 15 | 40 | 0.79 % | 0.09 | 0.07 | Pilar C-25 - Retangular 15x40
P18 | 05. Pavimento Técnico | retangular | 15 | 40 | 1.05 % | 0.07 | 0.06 | Pilar C-25 - Retangular 15x40
P19 | 05. Pavimento Técnico | retangular | 15 | 40 | 0.79 % | 0.14 | 0.12 | Pilar C-25 - Retangular 15x40
P2 | 05. Pavimento Técnico | retangular | 15 | 40 | 0.79 % | 0.02 | 0.02 | Pilar C-25 - Retangular 15x40
P20 | 05. Pavimento Técnico | retangular | 20 | 40 | 1.01 % | 0.09 | 0.07 | Pilar C-25 - Retangular 20x40
P21 | 05. Pavimento Técnico | retangular | 20 | 45 | 3.49 % | 0.3 | 0.19 | Pilar C-25 - Retangular 20x45
P22 | 05. Pavimento Técnico | retangular | 15 | 40 | 1.31 % | 0.03 | 0.02 | Pilar C-25 - Retangular 15x40
P23 | 05. Pavimento Técnico | retangular | 15 | 40 | 2.36 % | 0.03 | 0.03 | Pilar C-25 - Retangular 15x40
P28 | 05. Pavimento Técnico | seção circular | 5 | 45 | 0.65 % | 0.1 | 0.09 | Pilar C-25 - Seção Circular 45x5
P29 | 05. Pavimento Técnico | seção circular | 5 | 45 | 0.60 % | 0.07 | 0.06 | Pilar C-25 - Seção Circular 45x5
P3 | 05. Pavimento Técnico | retangular | 15 | 40 | 1.31 % | 0.03 | 0.02 | Pilar C-25 - Retangular 15x40
P30 | 05. Pavimento Técnico | seção circular | 5 | 45 | 1.28 % | 0.12 | 0.1 | Pilar C-25 - Seção Circular 45x5
P33 | 05. Pavimento Técnico | retangular | 15 | 40 | 3.27 % | 0.07 | 0.04 | Pilar C-25 - Retangular 15x40
P34 | 05. Pavimento Técnico | retangular | 15 | 40 | 2.01 % | 0.06 | 0.04 | Pilar C-25 - Retangular 15x40
P36 | 05. Pavimento Técnico | retangular | 15 | 40 | 1.57 % | 0.07 | 0.05 | Pilar C-25 - Retangular 15x40
P37 | 05. Pavimento Técnico | retangular | 15 | 40 | 1.23 % | 0.04 | 0.04 | Pilar C-25 - Retangular 15x40
P38 | 05. Pavimento Técnico | retangular | 15 | 40 | 0.79 % | 0.07 | 0.06 | Pilar C-25 - Retangular 15x40
P39 | 05. Pavimento Técnico | retangular | 15 | 40 | 4.02 % | 0.05 | 0.03 | Pilar C-25 - Retangular 15x40
P4 | 05. Pavimento Técnico | retangular | 15 | 40 | 0.79 % | 0.05 | 0.04 | Pilar C-25 - Retangular 15x40
P40 | 05. Pavimento Técnico | retangular | 20 | 40 | 4.52 % | 0.16 | 0.1 | Pilar C-25 - Retangular 20x40
P5 | 05. Pavimento Técnico | retangular | 20 | 40 | 0.59 % | 0.02 | 0.01 | Pilar C-25 - Retangular 20x40
P6 | 05. Pavimento Técnico | retangular | 20 | 40 | 1.23 % | 0.1 | 0.08 | Pilar C-25 - Retangular 20x40
P8 | 05. Pavimento Técnico | retangular | 20 | 45 | 3.27 % | 0.09 | 0.07 | Pilar C-25 - Retangular 20x45
P9 | 05. Pavimento Técnico | retangular | 20 | 45 | 1.36 % | 0.06 | 0.05 | Pilar C-25 - Retangular 20x45
P19 | 06. Laje do Pavimento Técnico | retangular | 15 | 40 | 0.79 % | 0.08 | 0.07 | Pilar C-25 - Retangular 15x40
P20 | 06. Laje do Pavimento Técnico | retangular | 20 | 40 | 1.37 % | 0.06 | 0.05 | Pilar C-25 - Retangular 20x40
P21 | 06. Laje do Pavimento Técnico | retangular | 20 | 40 | 1.37 % | 0.11 | 0.09 | Pilar C-25 - Retangular 20x40
P24 | 06. Laje do Pavimento Técnico | retangular | 20 | 40 | 0.59 % | 0.01 | 0.01 | Pilar C-25 - Retangular 20x40
P25 | 06. Laje do Pavimento Técnico | retangular | 20 | 40 | 0.98 % | 0 | 0 | Pilar C-25 - Retangular 20x40
P26 | 06. Laje do Pavimento Técnico | retangular | 20 | 40 | 3.37 % | 0 | 0 | Pilar C-25 - Retangular 20x40
P27 | 06. Laje do Pavimento Técnico | retangular | 20 | 40 | 0.92 % | 0.02 | 0.02 | Pilar C-25 - Retangular 20x40
P4 | 06. Laje do Pavimento Técnico | retangular | 15 | 40 | 1.05 % | 0.03 | 0.03 | Pilar C-25 - Retangular 15x40
P5 | 06. Laje do Pavimento Técnico | retangular | 20 | 40 | 1.57 % | 0.02 | 0.02 | Pilar C-25 - Retangular 20x40
P6 | 06. Laje do Pavimento Técnico | retangular | 20 | 40 | 0.79 % | 0.05 | 0.04 | Pilar C-25 - Retangular 20x40
P7 | 06. Laje do Pavimento Técnico | retangular | 15 | 40 | 1.57 % | 0.02 | 0.02 | Pilar C-25 - Retangular 15x40

# IfcFooting (35)
In: 01. Estacionamento
Material: Concreto
Pset_ConcreteElementGeneral - EnvironmentalClass: 2; ConstructionType: InSitu
AltoQi_Eberick_Elemento - Elemento: Bloco; Elevação: 0 cm
AltoQi_Eberick_Padrão - Cobrimento: 4.5 cm; Classe de concreto: C-25
Pset_PileCommon - Reference: Estaca circular R30 - Concreto C-25
Pset_FootingCommon - Reference: Bloco C-25
Name | Tipo | Seção_LB (cm) | Seção_LH (cm)
P1 | 3 LIN | 240 | 60
P10 | 3 TRI | 159.282 | 137.942
P11 | 1 | 60 | 60
P12 | 2 | 150 | 60
P13 | 2 | 150 | 60
P14 | 1 | 60 | 60
P15 | 8 RET | 330 | 150
P16 | 1 | 60 | 60
P17 | 3 TRI | 159.282 | 137.942
P18 | 3 TRI | 159.282 | 137.942
P19 | 3 TRI | 159.282 | 137.942
P2 | 1 | 60 | 60
P20 | 3 TRI | 159.282 | 137.942
P21 | 4 RET | 150 | 150
P22 | 1 | 60 | 60
P23 | 1 | 60 | 60
P28 | 5 RET | 187.279 | 187.279
P29 | 3 LIN | 240 | 60
P3 | 1 | 60 | 60
P30 | 5 RET | 187.279 | 187.279
P31 | 4 RET | 150 | 150
P32 | 4 RET | 150 | 150
P33 | 1 | 60 | 60
P34 | 3 TRI | 159.282 | 137.942
P35 | 1 | 60 | 60
P36 | 1 | 60 | 60
P37 | 1 | 60 | 60
P38 | 1 | 60 | 60
P39 | 3 TRI | 159.282 | 137.942
P4 | 1 | 60 | 60
P40 | 3 TRI | 159.282 | 137.942
P5 | 5 RET | 187.279 | 187.279
P6 | 4 RET | 150 | 150
P8 | 5 RET | 187.279 | 187.279
P9 | 4 RET | 150 | 150

# IfcPile (95)
In: 01. Estacionamento
Material: Concreto
Pset_ConcreteElementGeneral - EnvironmentalClass: 2; ConstructionType: InSitu
AltoQi_Eberick_Elemento - Elemento: Bloco; Elevação: 0 cm
AltoQi_Eberick_Padrão - Cobrimento: 4.5 cm; Classe de concreto: C-25
Pset_PileCommon - Reference: Estaca circular R30 - Concreto C-25
Pset_FootingCommon - Reference: Bloco C-25
Name | Tipo | Seção_LB (cm) | Seção_LH (cm)
E1-1 | 3 LIN | 240 | 60
E1-2 | 3 LIN | 240 | 60
E1-3 | 3 LIN | 240 | 60
E10-1 | 3 TRI | 159.282 | 137.942
E10-2 | 3 TRI | 159.282 | 137.942
E10-3 | 3 TRI | 159.282 | 137.942
E11-1 | 1 | 60 | 60
E12-1 | 2 | 150 | 60
E12-2 | 2 | 150 | 60
E13-1 | 2 | 150 | 60
E13-2 | 2 | 150 | 60
E14-1 | 1 | 60 | 60
E15-1 | 8 RET | 330 | 150
E15-2 | 8 RET | 330 | 150
E15-3 | 8 RET | 330 | 150
E15-4 | 8 RET | 330 | 150
E15-5 | 8 RET | 330 | 150
E15-6 | 8 RET | 330 | 150
E15-7 | 8 RET | 330 | 150
E15-8 | 8 RET | 330 | 150
E16-1 | 1 | 60 | 60
E17-1 | 3 TRI | 159.282 | 137.942
E17-2 | 3 TRI | 159.282 | 137.942
E17-3 | 3 TRI | 159.282 | 137.942
E18-1 | 3 TRI | 159.282 | 137.942
E18-2 | 3 TRI | 159.282 | 137.942
E18-3 | 3 TRI | 159.282 | 137.942
E19-1 | 3 TRI | 159.282 | 137.942
E19-2 | 3 TRI | 159.282 | 137.942
E19-3 | 3 TRI | 159.282 | 137.942
E2-1 | 1 | 60 | 60
E20-1 | 3 TRI | 159.282 | 137.942
E20-2 | 3 TRI | 159.282 | 137.942
E20-3 | 3 TRI | 159.282 | 137.942
E21-1 | 4 RET | 150 | 150
E21-2 | 4 RET | 150 | 150
E21-3 | 4 RET | 150 | 150
E21-4 | 4 RET | 150 | 150
E22-1 | 1 | 60 | 60
E23-1 | 1 | 60 | 60
E28-1 | 5 RET | 187.279 | 187.279
E28-2 | 5 RET | 187.279 | 187.279
E28-3 | 5 RET | 187.279 | 187.279
E28-4 | 5 RET | 187.279 | 187.279
E28-5 | 5 RET | 187.279 | 187.279
E29-1 | 3 LIN | 240 | 60
E29-2 | 3 LIN | 240 | 60
E29-3 | 3 LIN | 240 | 60
E3-1 | 1 | 60 | 60
E30-1 | 5 RET | 187.279 | 187.279
E30-2 | 5 RET | 187.279 | 187.279
E30-3 | 5 RET | 187.279 | 187.279
E30-4 | 5 RET | 187.279 | 187.279
E30-5 | 5 RET | 187.279 | 187.279
E31-1 | 4 RET | 150 | 150
E31-2 | 4 RET | 150 | 150
E31-3 | 4 RET | 150 | 150
E31-4 | 4 RET | 150 | 150
E32-1 | 4 RET | 150 | 150
E32-2 | 4 RET | 150 | 150
E32-3 | 4 RET | 150 | 150
E32-4 | 4 RET | 150 | 150
E33-1 | 1 | 60 | 60
E34-1 | 3 TRI | 159.282 | 137.942
E34-2 | 3 TRI | 159.282 | 137.942
E34-3 | 3 TRI | 159.282 | 137.942
E35-1 | 1 | 60 | 60
E36-1 | 1 | 60 | 60
E37-1 | 1 | 60 | 60
E38-1 | 1 | 60 | 60
E39-1 | 3 TRI | 159.282 | 137.942
E39-2 | 3 TRI | 159.282 | 137.942
E39-3 | 3 TRI | 159.282 | 137.942
E4-1 | 1 | 60 | 60
E40-1 | 3 TRI | 159.282 | 137.942
E40-2 | 3 TRI | 159.282 | 137.942
E40-3 | 3 TRI | 159.282 | 137.942
E5-1 | 5 RET | 187.279 | 187.279
E5-2 | 5 RET | 187.279 | 187.279
E5-3 | 5 RET | 187.279 | 187.279
E5-4 | 5 RET | 187.279 | 187.279
E5-5 | 5 RET | 187.279 | 187.279
E6-1 | 4 RET | 150 | 150
E6-2 | 4 RET | 150 | 150
E6-3 | 4 RET | 150 | 150
E6-4 | 4 RET | 150 | 150
E8-1 | 5 RET | 187.279 | 187.279
E8-2 | 5 RET | 187.279 | 187.279
E8-3 | 5 RET | 187.279 | 187.279
E8-4 | 5 RET | 187.279 | 187.279
E8-5 | 5 RET | 187.279 | 187.279
E9-1 | 4 RET | 150 | 150
E9-2 | 4 RET | 150 | 150
E9-3 | 4 RET | 150 | 150
E9-4 | 4 RET | 150 | 150

# IfcSlab (150)
PredefinedType: FLOOR; Material: Concreto
Pset_ConcreteElementGeneral - EnvironmentalClass: 2; ConstructionType: InSitu
AltoQi_Eberick_Elemento - Elemento: Laje; Elevação: 0 cm
AltoQi_Eberick_Padrão - Ambiente: Externo; Cobrimento: 2.5 cm; Classe de concreto: C-30
AltoQi_Eberick_Cargas - Adicional (G2): 0; Solo (S): 0; Água (A): 0; Subpressão (AS): 0
Pset_SlabCommon - LoadBearing: yes; IsExternal: yes; PitchAngle: 0 rad
Name | In | Tipo | Espessura (cm) | Revestimento (G2) | Acidental (Q) | Reference
L1 | 02. Térreo | Maciça | 12 | 154.5 | 300 | Laje Maciça - h=12cm
L10 | 02. Térreo | Alveolar | 20 | 154.5 | 300 | Laje Alveolar - h=20cm
L11 | 02. Térreo | Maciça | 20 | 154.5 | 300 | Laje Maciça - h=20cm
L12 | 02. Térreo | Maciça | 20 | 154.5 | 300 | Laje Maciça - h=20cm
L13 | 02. Térreo | Maciça | 12 | 154.5 | 300 | Laje Maciça - h=12cm
L14 | 02. Térreo | Maciça | 12 | 154.5 | 300 | Laje Maciça - h=12cm
L15 | 02. Térreo | Maciça | 12 | 154.5 | 300 | Laje Maciça - h=12cm
L16 | 02. Térreo | Maciça | 12 | 154.5 | 300 | Laje Maciça - h=12cm
L17 | 02. Térreo | Maciça | 12 | 154.5 | 300 | Laje Maciça - h=12cm
L18 | 02. Térreo | Maciça | 12 | 154.5 | 300 | Laje Maciça - h=12cm
L19 | 02. Térreo | Maciça | 13 | 181.5 | 150 | Laje Maciça - h=13cm
L2 | 02. Térreo | Maciça | 12 | 154.5 | 300 | Laje Maciça - h=12cm
L26 | 02. Térreo | Maciça | 12 | 154.5 | 300 | Laje Maciça - h=12cm
L27 | 02. Térreo | Maciça | 12 | 154.5 | 300 | Laje Maciça - h=12cm
L28 | 02. Térreo | Maciça | 12 | 154.5 | 300 | Laje Maciça - h=12cm
L29 | 02. Térreo | Maciça | 12 | 154.5 | 300 | Laje Maciça - h=12cm
L3 | 02. Térreo | Maciça | 12 | 154.5 | 300 | Laje Maciça - h=12cm
L4 | 02. Térreo | Maciça | 12 | 154.5 | 300 | Laje Maciça - h=12cm
L5 | 02. Térreo | Maciça | 12 | 154.5 | 300 | Laje Maciça - h=12cm
L6 | 02. Térreo | Alveolar | 20 | 154.5 | 300 | Laje Alveolar - h=20cm
L7 | 02. Térreo | Alveolar | 20 | 154.5 | 300 | Laje Alveolar - h=20cm
L8 | 02. Térreo | Alveolar | 20 | 154.5 | 300 | Laje Alveolar - h=20cm
L9 | 02. Térreo | Alveolar | 20 | 154.5 | 300 | Laje Alveolar - h=20cm
L1 | 03. Pavimento Superior | Maciça | 12 | 154.5 | 300 | Laje Maciça - h=12cm
L10 | 03. Pavimento Superior | Alveolar | 20 | 154.5 | 300 | Laje Alveolar - h=20cm
L11 | 03. Pavimento Superior | Alveolar | 20 | 154.5 | 300 | Laje Alveolar - h=20cm
L12 | 03. Pavimento Superior | Alveolar | 20 | 154.5 | 300 | Laje Alveolar - h=20cm
L13 | 03. Pavimento Superior | Alveolar | 20 | 154.5 | 300 | Laje Alveolar - h=20cm
L14 | 03. Pavimento Superior | Maciça | 12 | 154.5 | 300 | Laje Maciça - h=12cm
L15 | 03. Pavimento Superior | Maciça | 12 | 154.5 | 300 | Laje Maciça - h=12cm
L16 | 03. Pavimento Superior | Maciça | 12 | 154.5 | 300 | Laje Maciça - h=12cm
L17 | 03. Pavimento Superior | Maciça | 12 | 154.5 | 300 | Laje Maciça - h=12cm
L18 | 03. Pavimento Superior | Maciça | 12 | 154.5 | 300 | Laje Maciça - h=12cm
L19 | 03. Pavimento Superior | Maciça | 12 | 154.5 | 300 | Laje Maciça - h=12cm
L2 | 03. Pavimento Superior | Maciça | 12 | 154.5 | 300 | Laje Maciça - h=12cm
L20 | 03. Pavimento Superior | Maciça | 12 | 154.5 | 300 | Laje Maciça - h=12cm
L21 | 03. Pavimento Superior | Maciça | 12 | 154.5 | 300 | Laje Maciça - h=12cm
L22 | 03. Pavimento Superior | Maciça | 12 | 154.5 | 300 | Laje Maciça - h=12cm
L23 | 03. Pavimento Superior | Maciça | 12 | 154.5 | 300 | Laje Maciça - h=12cm
L24 | 03. Pavimento Superior | Maciça | 12 | 154.5 | 300 | Laje Maciça - h=12cm
L25 | 03. Pavimento Superior | Maciça | 12 | 154.5 | 300 | Laje Maciça - h=12cm
L26 | 03. Pavimento Superior | Maciça | 12 | 154.5 | 300 | Laje Maciça - h=12cm
L27 | 03. Pavimento Superior | Maciça | 12 | 154.5 | 300 | Laje Maciça - h=12cm
L28 | 03. Pavimento Superior | Maciça | 12 | 154.5 | 300 | Laje Maciça - h=12cm
L29 | 03. Pavimento Superior | Maciça | 12 | 154.5 | 300 | Laje Maciça - h=12cm
L3 | 03. Pavimento Superior | Maciça | 12 | 154.5 | 300 | Laje Maciça - h=12cm
L30 | 03. Pavimento Superior | Maciça | 12 | 154.5 | 300 | Laje Maciça - h=12cm
L31 | 03. Pavimento Superior | Maciça | 12 | 154.5 | 300 | Laje Maciça - h=12cm
L32 | 03. Pavimento Superior | Maciça | 12 | 154.5 | 300 | Laje Maciça - h=12cm
L33 | 03. Pavimento Superior | Maciça | 12 | 154.5 | 300 | Laje Maciça - h=12cm
L4 | 03. Pavimento Superior | Maciça | 12 | 154.5 | 300 | Laje Maciça - h=12cm
L5 | 03. Pavimento Superior | Maciça | 12 | 154.5 | 300 | Laje Maciça - h=12cm
L6 | 03. Pavimento Superior | Maciça | 12 | 154.5 | 300 | Laje Maciça - h=12cm
L7 | 03. Pavimento Superior | Maciça | 12 | 154.5 | 300 | Laje Maciça - h=12cm
L8 | 03. Pavimento Superior | Maciça | 12 | 154.5 | 300 | Laje Maciça - h=12cm
L9 | 03. Pavimento Superior | Maciça | 12 | 154.5 | 300 | Laje Maciça - h=12cm
L1 | 04. Cobertura | Maciça | 12 | 154.5 | 300 | Laje Maciça - h=12cm
L10 | 04. Cobertura | Alveolar | 20 | 154.5 | 300 | Laje Alveolar - h=20cm
L11 | 04. Cobertura | Alveolar | 20 | 154.5 | 300 | Laje Alveolar - h=20cm
L12 | 04. Cobertura | Maciça | 12 | 154.5 | 300 | Laje Maciça - h=12cm
L13 | 04. Cobertura | Maciça | 12 | 154.5 | 300 | Laje Maciça - h=12cm
L14 | 04. Cobertura | Maciça | 12 | 154.5 | 300 | Laje Maciça - h=12cm
L15 | 04. Cobertura | Maciça | 12 | 154.5 | 300 | Laje Maciça - h=12cm
L16 | 04. Cobertura | Maciça | 12 | 154.5 | 300 | Laje Maciça - h=12cm
L17 | 04. Cobertura | Maciça | 12 | 154.5 | 300 | Laje Maciça - h=12cm
L18 | 04. Cobertura | Maciça | 12 | 154.5 | 300 | Laje Maciça - h=12cm
L19 | 04. Cobertura | Maciça | 12 | 154.5 | 300 | Laje Maciça - h=12cm
L2 | 04. Cobertura | Maciça | 12 | 154.5 | 300 | Laje Maciça - h=12cm
L20 | 04. Cobertura | Maciça | 12 | 154.5 | 300 | Laje Maciça - h=12cm
L21 | 04. Cobertura | Maciça | 12 | 154.5 | 300 | Laje Maciça - h=12cm
L22 | 04. Cobertura | Maciça | 12 | 154.5 | 300 | Laje Maciça - h=12cm
L23 | 04. Cobertura | Maciça | 12 | 154.5 | 300 | Laje Maciça - h=12cm
L24 | 04. Cobertura | Maciça | 12 | 154.5 | 300 | Laje Maciça - h=12cm
L25 | 04. Cobertura | Maciça | 12 | 154.5 | 300 | Laje Maciça - h=12cm
L26 | 04. Cobertura | Maciça | 12 | 154.5 | 300 | Laje Maciça - h=12cm
L27 | 04. Cobertura | Maciça | 12 | 154.5 | 300 | Laje Maciça - h=12cm
L28 | 04. Cobertura | Maciça | 12 | 154.5 | 300 | Laje Maciça - h=12cm
L29 | 04. Cobertura | Maciça | 12 | 154.5 | 300 | Laje Maciça - h=12cm
L3 | 04. Cobertura | Maciça | 12 | 154.5 | 300 | Laje Maciça - h=12cm
L30 | 04. Cobertura | Maciça | 12 | 154.5 | 300 | Laje Maciça - h=12cm
L31 | 04. Cobertura | Maciça | 12 | 154.5 | 300 | Laje Maciça - h=12cm
L32 | 04. Cobertura | Maciça | 12 | 154.5 | 300 | Laje Maciça - h=12cm
L33 | 04. Cobertura | Maciça | 12 | 154.5 | 300 | Laje Maciça - h=12cm
L4 | 04. Cobertura | Maciça | 12 | 154.5 | 300 | Laje Maciça - h=12cm
L5 | 04. Cobertura | Maciça | 12 | 154.5 | 300 | Laje Maciça - h=12cm
L6 | 04. Cobertura | Maciça | 12 | 154.5 | 300 | Laje Maciça - h=12cm
L7 | 04. Cobertura | Maciça | 12 | 154.5 | 300 | Laje Maciça - h=12cm
L8 | 04. Cobertura | Maciça | 12 | 154.5 | 300 | Laje Maciça - h=12cm
L9 | 04. Cobertura | Alveolar | 20 | 154.5 | 300 | Laje Alveolar - h=20cm
L1 | 05. Pavimento Técnico | Maciça | 12 | 181.5 | 150 | Laje Maciça - h=12cm
L10 | 05. Pavimento Técnico | Maciça | 12 | 181.5 | 150 | Laje Maciça - h=12cm
L11 | 05. Pavimento Técnico | Maciça | 12 | 181.5 | 150 | Laje Maciça - h=12cm
L12 | 05. Pavimento Técnico | Maciça | 12 | 181.5 | 150 | Laje Maciça - h=12cm
L13 | 05. Pavimento Técnico | Maciça | 12 | 154.5 | 300 | Laje Maciça - h=12cm
L14 | 05. Pavimento Técnico | Maciça | 12 | 181.5 | 150 | Laje Maciça - h=12cm
L15 | 05. Pavimento Técnico | Maciça | 12 | 181.5 | 150 | Laje Maciça - h=12cm
L16 | 05. Pavimento Técnico | Maciça | 12 | 181.5 | 150 | Laje Maciça - h=12cm
L17 | 05. Pavimento Técnico | Maciça | 12 | 181.5 | 150 | Laje Maciça - h=12cm
L18 | 05. Pavimento Técnico | Maciça | 12 | 181.5 | 150 | Laje Maciça - h=12cm
L19 | 05. Pavimento Técnico | Maciça | 12 | 181.5 | 150 | Laje Maciça - h=12cm
L2 | 05. Pavimento Técnico | Maciça | 12 | 181.5 | 150 | Laje Maciça - h=12cm
L20 | 05. Pavimento Técnico | Maciça | 12 | 181.5 | 150 | Laje Maciça - h=12cm
L21 | 05. Pavimento Técnico | Maciça | 12 | 181.5 | 150 | Laje Maciça - h=12cm
L22 | 05. Pavimento Técnico | Maciça | 12 | 181.5 | 150 | Laje Maciça - h=12cm
L23 | 05. Pavimento Técnico | Maciça | 12 | 181.5 | 150 | Laje Maciça - h=12cm
L24 | 05. Pavimento Técnico | Maciça | 12 | 181.5 | 150 | Laje Maciça - h=12cm
L25 | 05. Pavimento Técnico | Maciça | 12 | 181.5 | 150 | Laje Maciça - h=12cm
L26 | 05. Pavimento Técnico | Maciça | 12 | 181.5 | 150 | Laje Maciça - h=12cm
L27 | 05. Pavimento Técnico | Maciça | 12 | 181.5 | 150 | Laje Maciça - h=12cm
L28 | 05. Pavimento Técnico | Maciça | 12 | 181.5 | 150 | Laje Maciça - h=12cm
L29 | 05. Pavimento Técnico | Maciça | 12 | 181.5 | 150 | Laje Maciça - h=12cm
L3 | 05. Pavimento Técnico | Maciça | 12 | 181.5 | 150 | Laje Maciça - h=12cm
L30 | 05. Pavimento Técnico | Maciça | 12 | 181.5 | 150 | Laje Maciça - h=12cm
L31 | 05. Pavimento Técnico | Maciça | 12 | 181.5 | 150 | Laje Maciça - h=12cm
L32 | 05. Pavimento Técnico | Maciça | 12 | 181.5 | 150 | Laje Maciça - h=12cm
L34 | 05. Pavimento Técnico | Maciça | 12 | 181.5 | 150 | Laje Maciça - h=12cm
L35 | 05. Pavimento Técnico | Maciça | 12 | 181.5 | 150 | Laje Maciça - h=12cm
L36 | 05. Pavimento Técnico | Maciça | 12 | 181.5 | 150 | Laje Maciça - h=12cm
L37 | 05. Pavimento Técnico | Maciça | 12 | 181.5 | 150 | Laje Maciça - h=12cm
L38 | 05. Pavimento Técnico | Maciça | 12 | 181.5 | 150 | Laje Maciça - h=12cm
L39 | 05. Pavimento Técnico | Maciça | 12 | 181.5 | 150 | Laje Maciça - h=12cm
L4 | 05. Pavimento Técnico | Maciça | 12 | 181.5 | 150 | Laje Maciça - h=12cm
L40 | 05. Pavimento Técnico | Maciça | 12 | 181.5 | 150 | Laje Maciça - h=12cm
L41 | 05. Pavimento Técnico | Maciça | 12 | 181.5 | 150 | Laje Maciça - h=12cm
L42 | 05. Pavimento Técnico | Maciça | 12 | 181.5 | 150 | Laje Maciça - h=12cm
L43 | 05. Pavimento Técnico | Maciça | 12 | 181.5 | 150 | Laje Maciça - h=12cm
L44 | 05. Pavimento Técnico | Maciça | 12 | 181.5 | 150 | Laje Maciça - h=12cm
L45 | 05. Pavimento Técnico | Maciça | 12 | 181.5 | 150 | Laje Maciça - h=12cm
L46 | 05. Pavimento Técnico | Maciça | 12 | 181.5 | 150 | Laje Maciça - h=12cm
L47 | 05. Pavimento Técnico | Maciça | 12 | 181.5 | 150 | Laje Maciça - h=12cm
L48 | 05. Pavimento Técnico | Maciça | 12 | 181.5 | 150 | Laje Maciça - h=12cm
L49 | 05. Pavimento Técnico | Maciça | 12 | 181.5 | 150 | Laje Maciça - h=12cm
L5 | 05. Pavimento Técnico | Maciça | 12 | 181.5 | 150 | Laje Maciça - h=12cm
L50 | 05. Pavimento Técnico | Maciça | 12 | 181.5 | 150 | Laje Maciça - h=12cm
L6 | 05. Pavimento Técnico | Maciça | 12 | 181.5 | 150 | Laje Maciça - h=12cm
L7 | 05. Pavimento Técnico | Maciça | 12 | 181.5 | 150 | Laje Maciça - h=12cm
L8 | 05. Pavimento Técnico | Maciça | 12 | 181.5 | 150 | Laje Maciça - h=12cm
L9 | 05. Pavimento Técnico | Maciça | 12 | 181.5 | 150 | Laje Maciça - h=12cm
L1 | 06. Laje do Pavimento Técnico | Maciça | 12 | 181.5 | 150 | Laje Maciça - h=12cm
L10 | 06. Laje do Pavimento Técnico | Maciça | 12 | 181.5 | 150 | Laje Maciça - h=12cm
L11 | 06. Laje do Pavimento Técnico | Maciça | 12 | 181.5 | 150 | Laje Maciça - h=12cm
L12 | 06. Laje do Pavimento Técnico | Maciça | 12 | 181.5 | 150 | Laje Maciça - h=12cm
L2 | 06. Laje do Pavimento Técnico | Maciça | 12 | 181.5 | 150 | Laje Maciça - h=12cm
L3 | 06. Laje do Pavimento Técnico | Maciça | 12 | 181.5 | 150 | Laje Maciça - h=12cm
L4 | 06. Laje do Pavimento Técnico | Maciça | 12 | 181.5 | 150 | Laje Maciça - h=12cm
L5 | 06. Laje do Pavimento Técnico | Maciça | 12 | 181.5 | 150 | Laje Maciça - h=12cm
L6 | 06. Laje do Pavimento Técnico | Maciça | 12 | 181.5 | 150 | Laje Maciça - h=12cm
L7 | 06. Laje do Pavimento Técnico | Maciça | 12 | 181.5 | 150 | Laje Maciça - h=12cm
L8 | 06. Laje do Pavimento Técnico | Maciça | 12 | 181.5 | 150 | Laje Maciça - h=12cm
L9 | 06. Laje do Pavimento Técnico | Maciça | 12 | 181.5 | 150 | Laje Maciça - h=12cm
